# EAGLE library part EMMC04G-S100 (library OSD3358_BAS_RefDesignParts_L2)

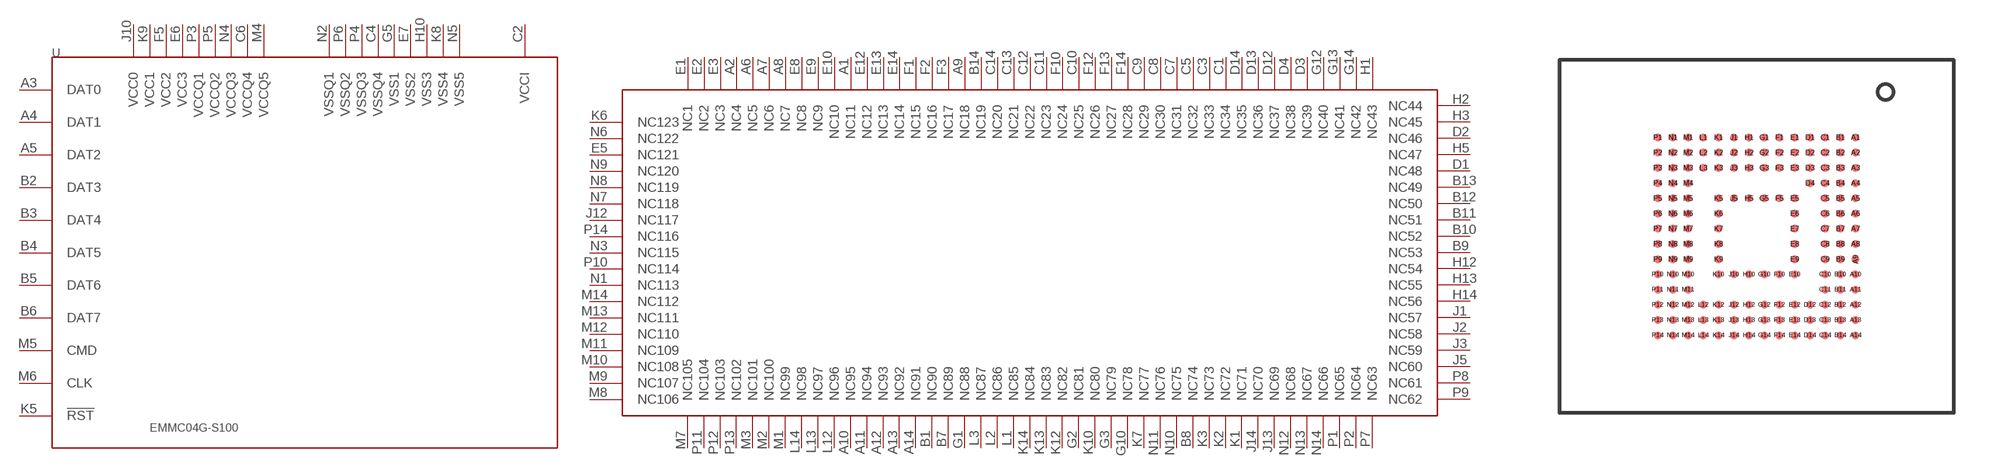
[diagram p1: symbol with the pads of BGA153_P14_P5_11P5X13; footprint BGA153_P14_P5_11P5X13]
Designator prefix U

## EMMC04G-S100  [BGA153_P14_P5_11P5X13]
A1  NC11  nc
A2  NC4  nc
A3  DAT0
A4  DAT1
A5  DAT2
A6  NC5  nc
A7  NC6  nc
A8  NC7  nc
A9  NC18  nc
A10  NC95  nc
A11  NC94  nc
A12  NC93  nc
A13  NC92  nc
A14  NC91  nc
B1  NC90  nc
B2  DAT3
B3  DAT4
B4  DAT5
B5  DAT6
B6  DAT7
B7  NC89  nc
B8  NC74  nc
B9  NC53  nc
B10  NC52  nc
B11  NC51  nc
B12  NC50  nc
B13  NC49  nc
B14  NC19  nc
C1  NC34  nc
C2  VCCI  pwr
C3  NC33  nc
C4  VSSQ4  pwr
C5  NC32  nc
C6  VCCQ4  pwr
C7  NC31  nc
C8  NC30  nc
C9  NC29  nc
C10  NC25  nc
C11  NC23  nc
C12  NC22  nc
C13  NC21  nc
C14  NC20  nc
D1  NC48  nc
D2  NC46  nc
D3  NC39  nc
D4  NC38  nc
D12  NC37  nc
D13  NC36  nc
D14  NC35  nc
E1  NC1  nc
E2  NC2  nc
E3  NC3  nc
E5  NC121  nc
E6  VCC3  pwr
E7  VSS2  pwr
E8  NC8  nc
E9  NC9  nc
E10  NC10  nc
E12  NC12  nc
E13  NC13  nc
E14  NC14  nc
F1  NC15  nc
F2  NC16  nc
F3  NC17  nc
F5  VCC2  pwr
F10  NC24  nc
F12  NC26  nc
F13  NC27  nc
F14  NC28  nc
G1  NC88  nc
G2  NC81  nc
G3  NC79  nc
G5  VSS1  pwr
G10  NC78  nc
G12  NC40  nc
G13  NC41  nc
G14  NC42  nc
H1  NC43  nc
H2  NC44  nc
H3  NC45  nc
H5  NC47  nc
H10  VSS3  pwr
H12  NC54  nc
H13  NC55  nc
H14  NC56  nc
J1  NC57  nc
J2  NC58  nc
J3  NC59  nc
J5  NC60  nc
J10  VCC0  pwr
J12  NC117  nc
J13  NC69  nc
J14  NC70  nc
K1  NC71  nc
K2  NC72  nc
K3  NC73  nc
K5  !RST  in
K6  NC123  nc
K7  NC77  nc
K8  VSS4  pwr
K9  VCC1  pwr
K10  NC80  nc
K12  NC82  nc
K13  NC83  nc
K14  NC84  nc
L1  NC85  nc
L2  NC86  nc
L3  NC87  nc
L12  NC96  nc
L13  NC97  nc
L14  NC98  nc
M1  NC99  nc
M2  NC100  nc
M3  NC101  nc
M4  VCCQ5  pwr
M5  CMD  in
M6  CLK  in
M7  NC105  nc
M8  NC106  nc
M9  NC107  nc
M10  NC108  nc
M11  NC109  nc
M12  NC110  nc
M13  NC111  nc
M14  NC112  nc
N1  NC113  nc
N2  VSSQ1  pwr
N3  NC115  nc
N4  VCCQ3  pwr
N5  VSS5  pwr
N6  NC122  nc
N7  NC118  nc
N8  NC119  nc
N9  NC120  nc
N10  NC75  nc
N11  NC76  nc
N12  NC68  nc
N13  NC67  nc
N14  NC66  nc
P1  NC65  nc
P2  NC64  nc
P3  VCCQ1  pwr
P4  VSSQ3  pwr
P5  VCCQ2  pwr
P6  VSSQ2  pwr
P7  NC63  nc
P8  NC61  nc
P9  NC62  nc
P10  NC114  nc
P11  NC104  nc
P12  NC103  nc
P13  NC102  nc
P14  NC116  nc

## Footprint BGA153_P14_P5_11P5X13 (pad centres in mm)
smd 0.254 x 0.254: A1 3.25,3.25; A2 3.25,2.75; A3 3.25,2.25; A4 3.25,1.75; A5 3.25,1.25; A6 3.25,0.75; A7 3.25,0.25; A8 3.25,-0.25; A9 3.25,-0.75; A10 3.25,-1.25; A11 3.25,-1.75; A12 3.25,-2.25; A13 3.25,-2.75; A14 3.25,-3.25; B1 2.75,3.25; B2 2.75,2.75; B3 2.75,2.25; B4 2.75,1.75; B5 2.75,1.25; B6 2.75,0.75; B7 2.75,0.25; B8 2.75,-0.25; B9 2.75,-0.75; B10 2.75,-1.25; B11 2.75,-1.75; B12 2.75,-2.25; B13 2.75,-2.75; B14 2.75,-3.25; C1 2.25,3.25; C2 2.25,2.75; C3 2.25,2.25; C4 2.25,1.75; C5 2.25,1.25; C6 2.25,0.75; C7 2.25,0.25; C8 2.25,-0.25; C9 2.25,-0.75; C10 2.25,-1.25; C11 2.25,-1.75; C12 2.25,-2.25; C13 2.25,-2.75; C14 2.25,-3.25; D1 1.75,3.25; D2 1.75,2.75; D3 1.75,2.25; D4 1.75,1.75; D12 1.75,-2.25; D13 1.75,-2.75; D14 1.75,-3.25; E1 1.25,3.25; E2 1.25,2.75; E3 1.25,2.25; E5 1.25,1.25; E6 1.25,0.75; E7 1.25,0.25; E8 1.25,-0.25; E9 1.25,-0.75; E10 1.25,-1.25; E12 1.25,-2.25; E13 1.25,-2.75; E14 1.25,-3.25; F1 0.75,3.25; F2 0.75,2.75; F3 0.75,2.25; F5 0.75,1.25; F10 0.75,-1.25; F12 0.75,-2.25; F13 0.75,-2.75; F14 0.75,-3.25; G1 0.25,3.25; G2 0.25,2.75; G3 0.25,2.25; G5 0.25,1.25; G10 0.25,-1.25; G12 0.25,-2.25; G13 0.25,-2.75; G14 0.25,-3.25; H1 -0.25,3.25; H2 -0.25,2.75; H3 -0.25,2.25; H5 -0.25,1.25; H10 -0.25,-1.25; H12 -0.25,-2.25; H13 -0.25,-2.75; H14 -0.25,-3.25; J1 -0.75,3.25; J2 -0.75,2.75; J3 -0.75,2.25; J5 -0.75,1.25; J10 -0.75,-1.25; J12 -0.75,-2.25; J13 -0.75,-2.75; J14 -0.75,-3.25; K1 -1.25,3.25; K2 -1.25,2.75; K3 -1.25,2.25; K5 -1.25,1.25; K6 -1.25,0.75; K7 -1.25,0.25; K8 -1.25,-0.25; K9 -1.25,-0.75; K10 -1.25,-1.25; K12 -1.25,-2.25; K13 -1.25,-2.75; K14 -1.25,-3.25; L1 -1.75,3.25; L2 -1.75,2.75; L3 -1.75,2.25; L12 -1.75,-2.25; L13 -1.75,-2.75; L14 -1.75,-3.25; M1 -2.25,3.25; M2 -2.25,2.75; M3 -2.25,2.25; M4 -2.25,1.75; M5 -2.25,1.25; M6 -2.25,0.75; M7 -2.25,0.25; M8 -2.25,-0.25; M9 -2.25,-0.75; M10 -2.25,-1.25; M11 -2.25,-1.75; M12 -2.25,-2.25; M13 -2.25,-2.75; M14 -2.25,-3.25; N1 -2.75,3.25; N2 -2.75,2.75; N3 -2.75,2.25; N4 -2.75,1.75; N5 -2.75,1.25; N6 -2.75,0.75; N7 -2.75,0.25; N8 -2.75,-0.25; N9 -2.75,-0.75; N10 -2.75,-1.25; N11 -2.75,-1.75; N12 -2.75,-2.25; N13 -2.75,-2.75; N14 -2.75,-3.25; P1 -3.25,3.25; P2 -3.25,2.75; P3 -3.25,2.25; P4 -3.25,1.75; P5 -3.25,1.25; P6 -3.25,0.75; P7 -3.25,0.25; P8 -3.25,-0.25; P9 -3.25,-0.75; P10 -3.25,-1.25; P11 -3.25,-1.75; P12 -3.25,-2.25; P13 -3.25,-2.75; P14 -3.25,-3.25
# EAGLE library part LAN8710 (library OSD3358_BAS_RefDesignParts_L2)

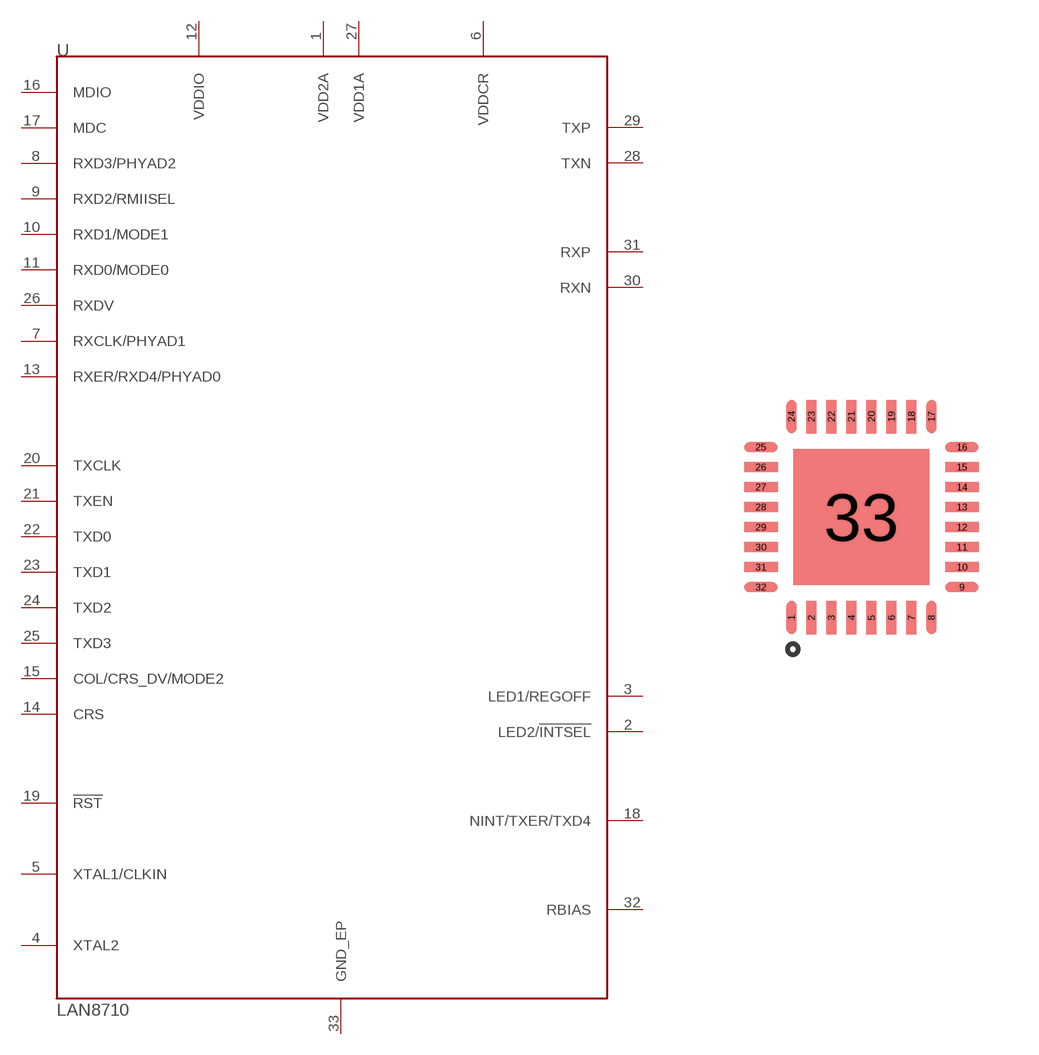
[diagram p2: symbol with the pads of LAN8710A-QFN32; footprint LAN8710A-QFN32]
Designator prefix U

## LAN8710  [LAN8710A-QFN32]
1  VDD2A  pwr
2  LED2/!INTSEL
3  LED1/REGOFF
4  XTAL2  in
5  XTAL1/CLKIN  in
6  VDDCR  pwr
7  RXCLK/PHYAD1
8  RXD3/PHYAD2
9  RXD2/RMIISEL
10  RXD1/MODE1
11  RXD0/MODE0
12  VDDIO  pwr
13  RXER/RXD4/PHYAD0
14  CRS
15  COL/CRS_DV/MODE2
16  MDIO
17  MDC  in
18  NINT/TXER/TXD4
19  !RST
20  TXCLK
21  TXEN  in
22  TXD0  in
23  TXD1  in
24  TXD2  in
25  TXD3  in
26  RXDV
27  VDD1A  pwr
28  TXN
29  TXP
30  RXN
31  RXP
32  RBIAS  pas
33  GND_EP  pwr

## Footprint LAN8710A-QFN32 (pad centres in mm)
smd 0.254 x 0.838: 1 -1.751,-2.515; 2 -1.251,-2.515; 3 -0.751,-2.515; 4 -0.251,-2.515; 5 0.251,-2.515; 6 0.751,-2.515; 7 1.251,-2.515; 8 1.751,-2.515; 17 1.751,2.515; 18 1.251,2.515; 19 0.751,2.515; 20 0.251,2.515; 21 -0.251,2.515; 22 -0.751,2.515; 23 -1.251,2.515; 24 -1.751,2.515
smd 0.838 x 0.254: 9 2.515,-1.751; 10 2.515,-1.251; 11 2.515,-0.751; 12 2.515,-0.251; 13 2.515,0.251; 14 2.515,0.751; 15 2.515,1.251; 16 2.515,1.751; 25 -2.515,1.751; 26 -2.515,1.251; 27 -2.515,0.751; 28 -2.515,0.251; 29 -2.515,-0.251; 30 -2.515,-0.751; 31 -2.515,-1.251; 32 -2.515,-1.751
smd 3.404 x 3.404: 33 0,0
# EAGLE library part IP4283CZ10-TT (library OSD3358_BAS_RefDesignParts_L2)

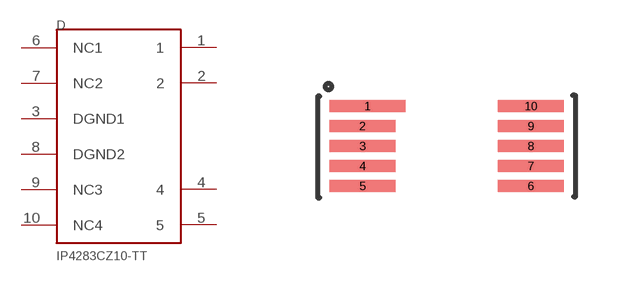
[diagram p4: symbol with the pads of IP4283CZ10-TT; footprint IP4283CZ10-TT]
Designator prefix D

## IP4283CZ10-TT  [IP4283CZ10-TT]
1  1
2  2
3  DGND1
4  4
5  5
6  NC1
7  NC2
8  DGND2
9  NC3
10  NC4

## Footprint IP4283CZ10-TT (pad centres in mm)
smd 1.905 x 0.305: 1 -1.981,1
smd 1.651 x 0.305: 2 -2.108,0.5; 3 -2.108,0; 4 -2.108,-0.5; 5 -2.108,-1; 6 2.108,-1; 7 2.108,-0.5; 8 2.108,0; 9 2.108,0.5; 10 2.108,1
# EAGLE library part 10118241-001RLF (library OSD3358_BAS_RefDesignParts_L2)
Micro-HDMI connector

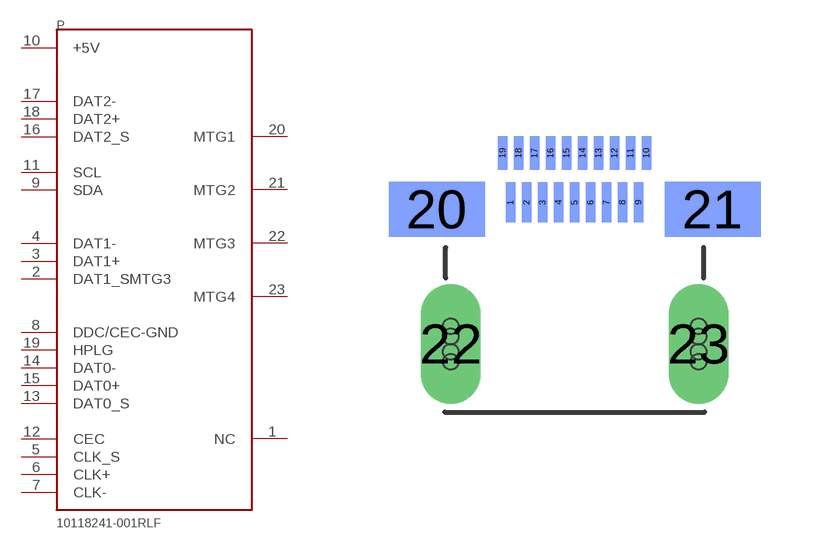
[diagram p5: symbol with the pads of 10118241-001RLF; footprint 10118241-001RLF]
Designator prefix P

## 10118241-001RLF  [10118241-001RLF]
1  NC  nc
2  DAT1_SMTG3
3  DAT1+
4  DAT1-
5  CLK_S
6  CLK+
7  CLK-
8  DDC/CEC-GND
9  SDA
10  +5V  pwr
11  SCL
12  CEC
13  DAT0_S
14  DAT0-
15  DAT0+
16  DAT2_S
17  DAT2-
18  DAT2+
19  HPLG
20  MTG1  pwr
21  MTG2  pwr
22  MTG3  pwr
23  MTG4  pwr

## Footprint 10118241-001RLF (pad centres in mm)
smd 0.23 x 1 bottom: 1 -1.6,3.54; 2 -1.2,3.54; 3 -0.8,3.54; 4 -0.4,3.54; 5 0,3.54; 6 0.4,3.54; 7 0.8,3.54; 8 1.2,3.54; 9 1.6,3.54
smd 0.23 x 0.85 bottom: 10 1.8,4.775; 11 1.4,4.775; 12 1,4.775; 13 0.6,4.775; 14 0.2,4.775; 15 -0.2,4.775; 16 -0.6,4.775; 17 -1,4.775; 18 -1.4,4.775; 19 -1.8,4.775
smd 2.4 x 1.38 bottom: 20 -3.45,3.37; 21 3.45,3.37
drill 0.381 pad 1.499 long: 22 -3.1,0; 23 3.1,0
hole 0.381 at -3.1,0.445
hole 0.381 at -3.1,0.191
hole 0.381 at -3.1,-0.191
hole 0.381 at -3.1,-0.445
hole 0.381 at 3.1,0.445
hole 0.381 at 3.1,0.191
hole 0.381 at 3.1,-0.191
hole 0.381 at 3.1,-0.445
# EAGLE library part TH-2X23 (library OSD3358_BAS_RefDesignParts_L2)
320030002

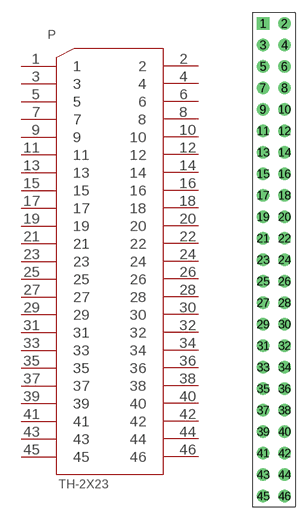
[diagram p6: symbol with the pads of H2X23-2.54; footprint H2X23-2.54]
Designator prefix P

## TH-2X23 (MPN: F185-1223A0ASYC1; VALUE: F185-1223A0ASYC1)  [H2X23-2.54]
1  1
2  2
3  3
4  4
5  5
6  6
7  7
8  8
9  9
10  10
11  11
12  12
13  13
14  14
15  15
16  16
17  17
18  18
19  19
20  20
21  21
22  22
23  23
24  24
25  25
26  26
27  27
28  28
29  29
30  30
31  31
32  32
33  33
34  34
35  35
36  36
37  37
38  38
39  39
40  40
41  41
42  42
43  43
44  44
45  45
46  46

## Footprint H2X23-2.54 (pad centres in mm)
drill 0.762 pad 1.524 square: 1 -1.27,27.94
drill 0.762 pad 1.524: 2 1.27,27.94; 3 -1.27,25.4; 4 1.27,25.4; 5 -1.27,22.86; 6 1.27,22.86; 7 -1.27,20.32; 8 1.27,20.32; 9 -1.27,17.78; 10 1.27,17.78; 11 -1.27,15.24; 12 1.27,15.24; 13 -1.27,12.7; 14 1.27,12.7; 15 -1.27,10.16; 16 1.27,10.16; 17 -1.27,7.62; 18 1.27,7.62; 19 -1.27,5.08; 20 1.27,5.08; 21 -1.27,2.54; 22 1.27,2.54; 23 -1.27,0; 24 1.27,0; 25 -1.27,-2.54; 26 1.27,-2.54; 27 -1.27,-5.08; 28 1.27,-5.08; 29 -1.27,-7.62; 30 1.27,-7.62; 31 -1.27,-10.16; 32 1.27,-10.16; 33 -1.27,-12.7; 34 1.27,-12.7; 35 -1.27,-15.24; 36 1.27,-15.24; 37 -1.27,-17.78; 38 1.27,-17.78; 39 -1.27,-20.32; 40 1.27,-20.32; 41 -1.27,-22.86; 42 1.27,-22.86; 43 -1.27,-25.4; 44 1.27,-25.4; 45 -1.27,-27.94; 46 1.27,-27.94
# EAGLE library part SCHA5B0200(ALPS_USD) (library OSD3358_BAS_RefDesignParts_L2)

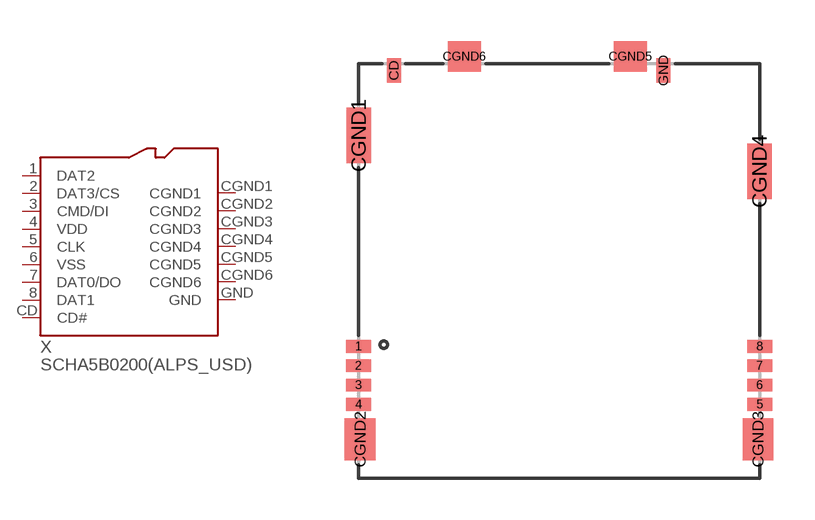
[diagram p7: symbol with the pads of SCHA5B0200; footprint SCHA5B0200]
Designator prefix X

## SCHA5B0200(ALPS_USD)  [SCHA5B0200]
1  DAT2
2  DAT3/CS
3  CMD/DI
4  VDD
5  CLK
6  VSS
7  DAT0/DO
8  DAT1
CD  CD#
CGND1  CGND1
CGND2  CGND2
CGND3  CGND3
CGND4  CGND4
CGND5  CGND5
CGND6  CGND6
GND  GND

## Footprint SCHA5B0200 (pad centres in mm)
smd 0.915 x 0.458: 1 -7.257,3.365; 2 -7.257,2.665; 3 -7.257,1.965; 4 -7.257,1.265; 5 7.257,1.265; 6 7.257,1.965; 7 7.257,2.665; 8 7.257,3.365
smd 0.51 x 0.887: CD -5.975,13.354; GND 3.775,13.354
smd 0.891 x 2.007: CGND1 -7.25,11; CGND4 7.25,9.7
smd 1.117 x 1.525: CGND2 -7.196,0; CGND3 7.196,0
smd 1.192 x 1.092: CGND5 2.575,13.853; CGND6 -3.425,13.853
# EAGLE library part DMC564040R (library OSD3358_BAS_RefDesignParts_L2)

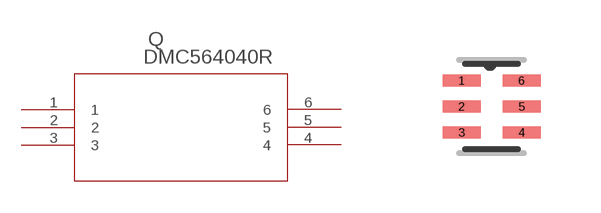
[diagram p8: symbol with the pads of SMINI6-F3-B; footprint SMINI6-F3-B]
Designator prefix Q

## DMC564040R (COPYRIGHT: Copyright (C) 2015 Accelerated Designs. All rights reserved; MANUFACTURER_PART_NUMBER: DMC564040R; VENDOR: Panasonic)  [SMINI6-F3-B]
1  1  pas
2  2  pas
3  3  pas
4  4  pas
5  5  pas
6  6  pas

## Footprint SMINI6-F3-B (pad centres in mm)
smd 0.95 x 0.305: 1 -0.75,0.65; 2 -0.75,0; 3 -0.75,-0.65; 4 0.75,-0.65; 5 0.75,0; 6 0.75,0.65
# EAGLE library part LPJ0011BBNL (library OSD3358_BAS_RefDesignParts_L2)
Ethernet Connector MagJack (R) Source: www.stewartconnector.com .. si-50170.pdf

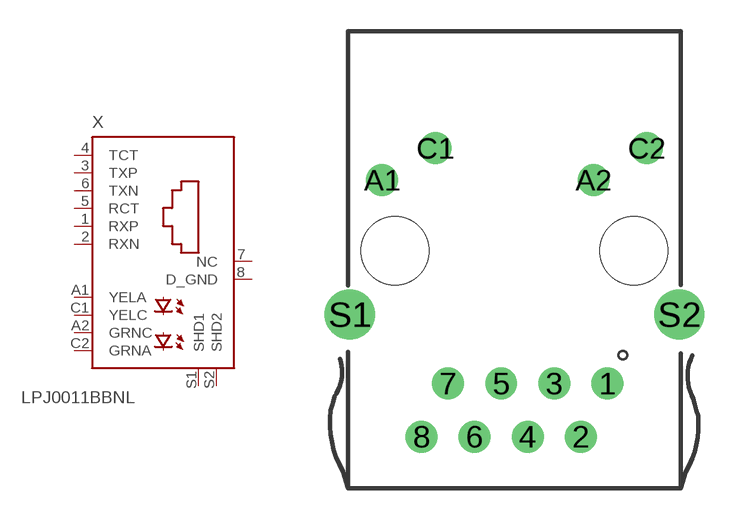
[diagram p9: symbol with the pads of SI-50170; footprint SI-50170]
Designator prefix X

## LPJ0011BBNL (OC_FARNELL: unknown; OC_NEWARK: unknown)  [SI-50170]
1  RXP  pas
2  RXN  pas
3  TXP  pas
4  TCT  pas
5  RCT  pas
6  TXN  pas
7  NC  pas
8  D_GND  pas
A1  YELA  pas
A2  GRNC  pas
C1  YELC  pas
C2  GRNA  pas
S1  SHD1  pas
S2  SHD2  pas

## Footprint SI-50170 (pad centres in mm)
Ethernet Connector (MagJack) Source: si-50170.pdf
drill 1.016 pad 1.524: 1 4.445,-6.413; 2 3.175,-8.954; 3 1.905,-6.413; 4 0.635,-8.954; 5 -0.635,-6.413; 6 -1.905,-8.954; 7 -3.175,-6.413; 8 -4.445,-8.954; A1 -6.325,3.315; A2 3.785,3.315; C1 -3.785,4.839; C2 6.325,4.839
drill 1.6 pad 2.286: S1 -7.874,-3.111; S2 7.874,-3.111
hole 3.251 at -5.715,-0.064
hole 3.251 at 5.715,-0.064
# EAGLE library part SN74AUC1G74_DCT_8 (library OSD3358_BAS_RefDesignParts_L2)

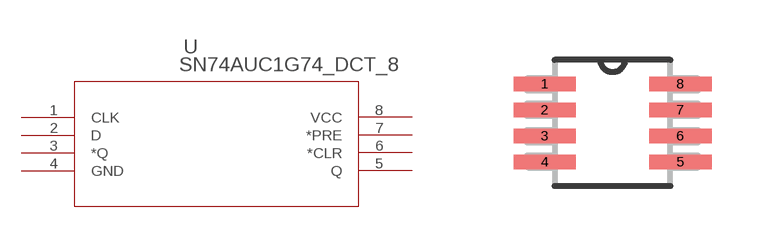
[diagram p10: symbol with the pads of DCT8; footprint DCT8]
Designator prefix U

## SN74AUC1G74_DCT_8 (DATASHEETURL: http://www.ti.com/lit/gpn/SN74AUC1G74; FAMILY_NAME: LL FLIP-FLOP; GENERIC_PART_NUMBER: SN74AUC1G74; INDUSTRY_STD_PKG_TYPE: SM8; MANUFACTURER: Texas Instruments; MANUFACTURER_PART_NUMBER: sn74auc1g74_dct_8; PACKAGE_DESIGNATOR: DCT; PIN_COUNT: 8; VENDOR: Texas Instruments)  [DCT8]
1  CLK  in
2  D  in
3  *Q  out
4  GND  pwr
5  Q  out
6  *CLR  in
7  *PRE  in
8  VCC  pwr

## Footprint DCT8 (pad centres in mm)
smd 1.562 x 0.356: 1 -1.695,0.975; 2 -1.695,0.325; 3 -1.695,-0.325; 4 -1.695,-0.975; 5 1.695,-0.975; 6 1.695,-0.325; 7 1.695,0.325; 8 1.695,0.975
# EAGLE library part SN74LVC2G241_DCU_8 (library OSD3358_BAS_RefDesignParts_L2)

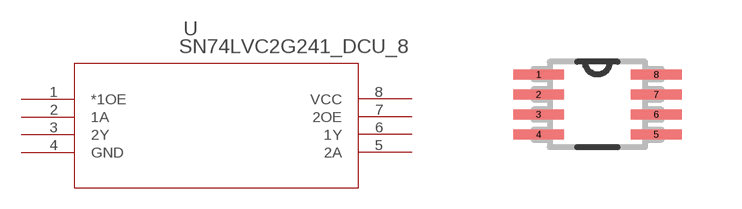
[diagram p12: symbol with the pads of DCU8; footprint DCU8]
Designator prefix U

## SN74LVC2G241_DCU_8 (DATASHEETURL: http://www.ti.com/lit/gpn/SN74LVC2G241; FAMILY_NAME: LL BUFFER AND DRIVER WITH 3-STATE OUTPUT; GENERIC_PART_NUMBER: SN74LVC2G241; INDUSTRY_STD_PKG_TYPE: US8; MANUFACTURER: Texas Instruments; MANUFACTURER_PART_NUMBER: sn74lvc2g241_dcu_8; PACKAGE_DESIGNATOR: DCU; PIN_COUNT: 8; VENDOR: Texas Instruments)  [DCU8]
1  *1OE  in
2  1A  in
3  2Y  out
4  GND  pwr
5  2A  in
6  1Y  out
7  2OE  in
8  VCC  pwr

## Footprint DCU8 (pad centres in mm)
smd 1.27 x 0.254: 1 -1.473,0.749; 2 -1.473,0.249; 3 -1.473,-0.249; 4 -1.473,-0.749; 5 1.473,-0.749; 6 1.473,-0.249; 7 1.473,0.249; 8 1.473,0.749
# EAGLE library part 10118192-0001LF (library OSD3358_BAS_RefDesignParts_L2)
Amphenol FCI Micro USB Type B Complete Surface Mount (SMT) no guide holes

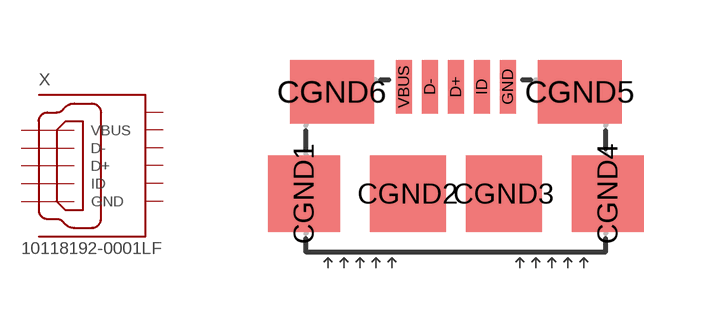
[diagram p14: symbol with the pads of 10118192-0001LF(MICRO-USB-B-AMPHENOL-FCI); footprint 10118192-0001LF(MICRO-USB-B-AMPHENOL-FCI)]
Designator prefix X

## 10118192-0001LF  [10118192-0001LF(MICRO-USB-B-AMPHENOL-FCI)]
CGND1  SGND1
CGND2  SGND2
CGND3  SGND3
CGND4  SGND4
CGND5  SGND5
CGND6  SGND6
D+  D+  in
D-  D-  in
GND  GND  in
ID  ID  in
VBUS  VBUS  in

## Footprint 10118192-0001LF(MICRO-USB-B-AMPHENOL-FCI) (pad centres in mm)
smd 1.8 x 1.9: CGND1 -3.8,0; CGND4 3.8,0
smd 1.9 x 1.9: CGND2 -1.2,0; CGND3 1.2,0
smd 2.1 x 1.6: CGND5 3.1,2.55; CGND6 -3.1,2.55
smd 0.4 x 1.35: D+ 0,2.675; D- -0.65,2.675; GND 1.3,2.675; ID 0.65,2.675; VBUS -1.3,2.675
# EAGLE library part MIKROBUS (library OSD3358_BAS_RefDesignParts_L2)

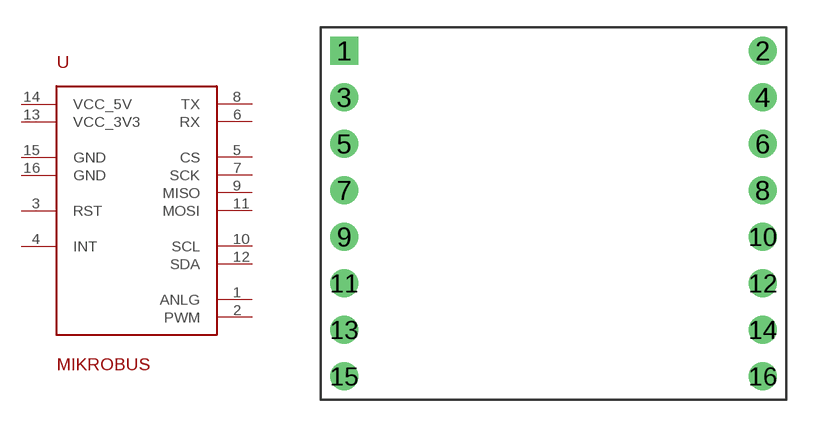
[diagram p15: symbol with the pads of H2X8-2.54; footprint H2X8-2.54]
Designator prefix -

## MIKROBUS  [H2X8-2.54]
1  ANLG
2  PWM
3  RST
4  INT
5  CS
6  RX
7  SCK
8  TX
9  MISO
10  SCL
11  MOSI
12  SDA
13  VCC_3V3
14  VCC_5V
15  GND
16  GND

## Footprint H2X8-2.54 (pad centres in mm)
drill 0.762 pad 1.524 square: 1 -11.684,8.89
drill 0.762 pad 1.524: 2 11.176,8.89; 3 -11.684,6.35; 4 11.176,6.35; 5 -11.684,3.81; 6 11.176,3.81; 7 -11.684,1.27; 8 11.176,1.27; 9 -11.684,-1.27; 10 11.176,-1.27; 11 -11.684,-3.81; 12 11.176,-3.81; 13 -11.684,-6.35; 14 11.176,-6.35; 15 -11.684,-8.89; 16 11.176,-8.89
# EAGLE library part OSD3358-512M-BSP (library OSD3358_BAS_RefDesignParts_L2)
Octavo Systems LLC OSD335x Family SiP: 21mm x 21mm, 1.27mm pitch 256 pin BGA contains AM3358, 512MB DDR3, TPS65217, TL5209, EEPROM and passives. Commerical Temperature: 0C to 85C.

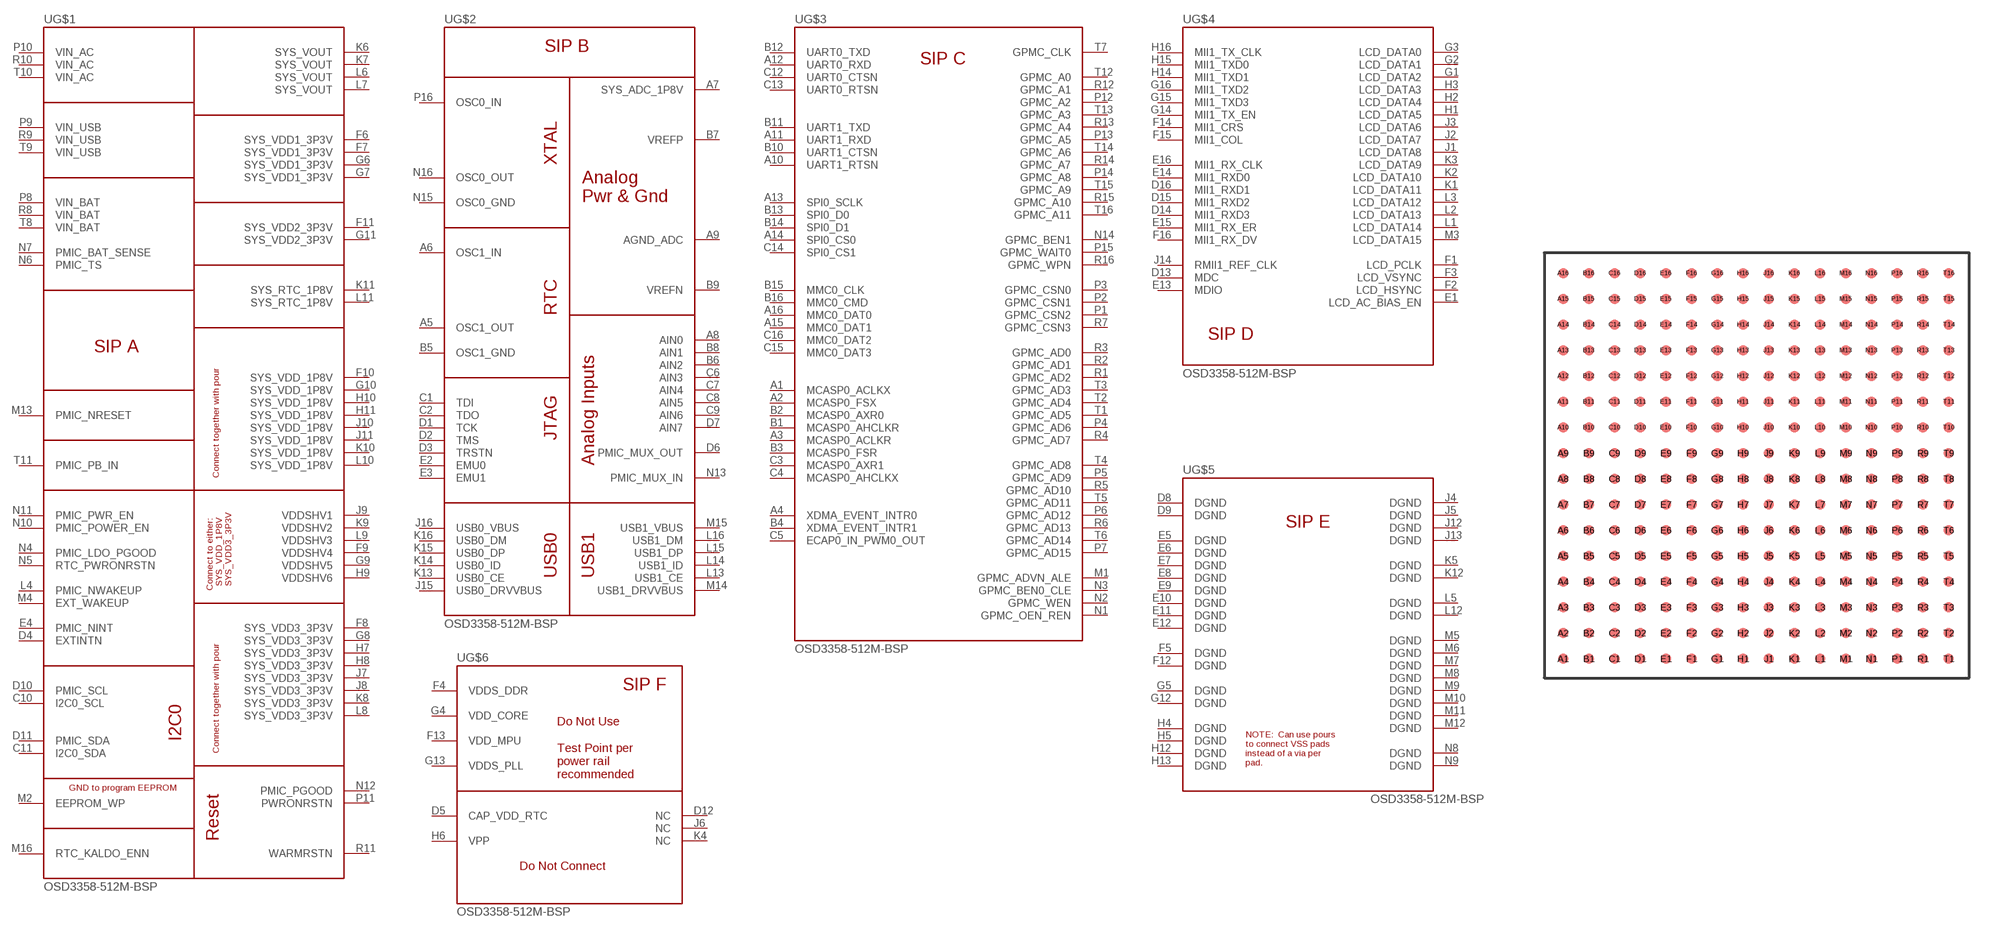
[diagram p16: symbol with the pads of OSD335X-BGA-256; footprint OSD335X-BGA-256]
Designator prefix -; gates G$1=OSD335X-SP-LOGICAL-A G$2=OSD335X-SP-LOGICAL-B G$3=OSD335X-SP-LOGICAL-C G$4=OSD335X-SP-LOGICAL-D G$5=OSD335X-SP-LOGICAL-E G$6=OSD335X-SP-LOGICAL-F

## OSD3358-512M-BSP  [OSD335X-BGA-256]
A1  G$3:MCASP0_ACLKX
A2  G$3:MCASP0_FSX
A3  G$3:MCASP0_ACLKR
A4  G$3:XDMA_EVENT_INTR0
A5  G$2:OSC1_OUT
A6  G$2:OSC1_IN
A7  G$2:SYS_ADC_1P8V
A8  G$2:AIN0
A9  G$2:AGND_ADC
A10  G$3:UART1_RTSN
A11  G$3:UART1_RXD
A12  G$3:UART0_RXD
A13  G$3:SPI0_SCLK
A14  G$3:SPI0_CS0
A15  G$3:MMC0_DAT1
A16  G$3:MMC0_DAT0
B1  G$3:MCASP0_AHCLKR
B2  G$3:MCASP0_AXR0
B3  G$3:MCASP0_FSR
B4  G$3:XDMA_EVENT_INTR1
B5  G$2:OSC1_GND
B6  G$2:AIN2
B7  G$2:VREFP
B8  G$2:AIN1
B9  G$2:VREFN
B10  G$3:UART1_CTSN
B11  G$3:UART1_TXD
B12  G$3:UART0_TXD
B13  G$3:SPI0_D0
B14  G$3:SPI0_D1
B15  G$3:MMC0_CLK
B16  G$3:MMC0_CMD
C1  G$2:TDI
C2  G$2:TDO
C3  G$3:MCASP0_AXR1
C4  G$3:MCASP0_AHCLKX
C5  G$3:ECAP0_IN_PWM0_OUT
C6  G$2:AIN3
C7  G$2:AIN4
C8  G$2:AIN5
C9  G$2:AIN6
C10  G$1:I2C0_SCL
C11  G$1:I2C0_SDA
C12  G$3:UART0_CTSN
C13  G$3:UART0_RTSN
C14  G$3:SPI0_CS1
C15  G$3:MMC0_DAT3
C16  G$3:MMC0_DAT2
D1  G$2:TCK
D2  G$2:TMS
D3  G$2:TRSTN
D4  G$1:EXTINTN
D5  G$6:CAP_VDD_RTC
D6  G$2:PMIC_MUX_OUT
D7  G$2:AIN7
D8  G$5:DGND
D9  G$5:DGND
D10  G$1:PMIC_SCL
D11  G$1:PMIC_SDA
D12  G$6:NC
D13  G$4:MDC
D14  G$4:MII1_RXD3
D15  G$4:MII1_RXD2
D16  G$4:MII1_RXD1
E1  G$4:LCD_AC_BIAS_EN
E2  G$2:EMU0
E3  G$2:EMU1
E4  G$1:PMIC_NINT  out
E5  G$5:DGND
E6  G$5:DGND
E7  G$5:DGND
E8  G$5:DGND
E9  G$5:DGND
E10  G$5:DGND
E11  G$5:DGND
E12  G$5:DGND
E13  G$4:MDIO
E14  G$4:MII1_RXD0
E15  G$4:MII1_RX_ER
E16  G$4:MII1_RX_CLK
F1  G$4:LCD_PCLK
F2  G$4:LCD_HSYNC
F3  G$4:LCD_VSYNC
F4  G$6:VDDS_DDR
F5  G$5:DGND
F6  G$1:SYS_VDD1_3P3V  pwr
F7  G$1:SYS_VDD1_3P3V  pwr
F8  G$1:SYS_VDD3_3P3V  pwr
F9  G$1:VDDSHV4  pwr
F10  G$1:SYS_VDD_1P8V  pwr
F11  G$1:SYS_VDD2_3P3V  pwr
F12  G$5:DGND
F13  G$6:VDD_MPU
F14  G$4:MII1_CRS
F15  G$4:MII1_COL
F16  G$4:MII1_RX_DV
G1  G$4:LCD_DATA2
G2  G$4:LCD_DATA1
G3  G$4:LCD_DATA0
G4  G$6:VDD_CORE
G5  G$5:DGND
G6  G$1:SYS_VDD1_3P3V  pwr
G7  G$1:SYS_VDD1_3P3V  pwr
G8  G$1:SYS_VDD3_3P3V  pwr
G9  G$1:VDDSHV5  pwr
G10  G$1:SYS_VDD_1P8V  pwr
G11  G$1:SYS_VDD2_3P3V  pwr
G12  G$5:DGND
G13  G$6:VDDS_PLL
G14  G$4:MII1_TX_EN
G15  G$4:MII1_TXD3
G16  G$4:MII1_TXD2
H1  G$4:LCD_DATA5
H2  G$4:LCD_DATA4
H3  G$4:LCD_DATA3
H4  G$5:DGND
H5  G$5:DGND
H6  G$6:VPP
H7  G$1:SYS_VDD3_3P3V  pwr
H8  G$1:SYS_VDD3_3P3V  pwr
H9  G$1:VDDSHV6  pwr
H10  G$1:SYS_VDD_1P8V  pwr
H11  G$1:SYS_VDD_1P8V  pwr
H12  G$5:DGND
H13  G$5:DGND
H14  G$4:MII1_TXD1
H15  G$4:MII1_TXD0
H16  G$4:MII1_TX_CLK
J1  G$4:LCD_DATA8
J2  G$4:LCD_DATA7
J3  G$4:LCD_DATA6
J4  G$5:DGND
J5  G$5:DGND
J6  G$6:NC
J7  G$1:SYS_VDD3_3P3V  pwr
J8  G$1:SYS_VDD3_3P3V  pwr
J9  G$1:VDDSHV1  pwr
J10  G$1:SYS_VDD_1P8V  pwr
J11  G$1:SYS_VDD_1P8V  pwr
J12  G$5:DGND
J13  G$5:DGND
J14  G$4:RMII1_REF_CLK
J15  G$2:USB0_DRVVBUS
J16  G$2:USB0_VBUS
K1  G$4:LCD_DATA11
K2  G$4:LCD_DATA10
K3  G$4:LCD_DATA9
K4  G$6:NC
K5  G$5:DGND
K6  G$1:SYS_VOUT  pwr
K7  G$1:SYS_VOUT  pwr
K8  G$1:SYS_VDD3_3P3V  pwr
K9  G$1:VDDSHV2  pwr
K10  G$1:SYS_VDD_1P8V  pwr
K11  G$1:SYS_RTC_1P8V  pwr
K12  G$5:DGND
K13  G$2:USB0_CE
K14  G$2:USB0_ID
K15  G$2:USB0_DP
K16  G$2:USB0_DM
L1  G$4:LCD_DATA14
L2  G$4:LCD_DATA13
L3  G$4:LCD_DATA12
L4  G$1:PMIC_NWAKEUP  out
L5  G$5:DGND
L6  G$1:SYS_VOUT  pwr
L7  G$1:SYS_VOUT  pwr
L8  G$1:SYS_VDD3_3P3V  pwr
L9  G$1:VDDSHV3  pwr
L10  G$1:SYS_VDD_1P8V  pwr
L11  G$1:SYS_RTC_1P8V  pwr
L12  G$5:DGND
L13  G$2:USB1_CE
L14  G$2:USB1_ID
L15  G$2:USB1_DP
L16  G$2:USB1_DM
M1  G$3:GPMC_ADVN_ALE
M2  G$1:EEPROM_WP
M3  G$4:LCD_DATA15
M4  G$1:EXT_WAKEUP
M5  G$5:DGND
M6  G$5:DGND
M7  G$5:DGND
M8  G$5:DGND
M9  G$5:DGND
M10  G$5:DGND
M11  G$5:DGND
M12  G$5:DGND
M13  G$1:PMIC_NRESET
M14  G$2:USB1_DRVVBUS
M15  G$2:USB1_VBUS
M16  G$1:RTC_KALDO_ENN
N1  G$3:GPMC_OEN_REN
N2  G$3:GPMC_WEN
N3  G$3:GPMC_BEN0_CLE
N4  G$1:PMIC_LDO_PGOOD  out
N5  G$1:RTC_PWRONRSTN
N6  G$1:PMIC_TS
N7  G$1:PMIC_BAT_SENSE
N8  G$5:DGND
N9  G$5:DGND
N10  G$1:PMIC_POWER_EN  out
N11  G$1:PMIC_PWR_EN  in
N12  G$1:PMIC_PGOOD  out
N13  G$2:PMIC_MUX_IN
N14  G$3:GPMC_BEN1
N15  G$2:OSC0_GND
N16  G$2:OSC0_OUT
P1  G$3:GPMC_CSN2
P2  G$3:GPMC_CSN1
P3  G$3:GPMC_CSN0
P4  G$3:GPMC_AD6
P5  G$3:GPMC_AD9
P6  G$3:GPMC_AD12
P7  G$3:GPMC_AD15
P8  G$1:VIN_BAT  pwr
P9  G$1:VIN_USB  pwr
P10  G$1:VIN_AC  pwr
P11  G$1:PWRONRSTN
P12  G$3:GPMC_A2
P13  G$3:GPMC_A5
P14  G$3:GPMC_A8
P15  G$3:GPMC_WAIT0
P16  G$2:OSC0_IN
R1  G$3:GPMC_AD2
R2  G$3:GPMC_AD1
R3  G$3:GPMC_AD0
R4  G$3:GPMC_AD7
R5  G$3:GPMC_AD10
R6  G$3:GPMC_AD13
R7  G$3:GPMC_CSN3
R8  G$1:VIN_BAT  pwr
R9  G$1:VIN_USB  pwr
R10  G$1:VIN_AC  pwr
R11  G$1:WARMRSTN
R12  G$3:GPMC_A1
R13  G$3:GPMC_A4
R14  G$3:GPMC_A7
R15  G$3:GPMC_A10
R16  G$3:GPMC_WPN
T1  G$3:GPMC_AD5
T2  G$3:GPMC_AD4
T3  G$3:GPMC_AD3
T4  G$3:GPMC_AD8
T5  G$3:GPMC_AD11
T6  G$3:GPMC_AD14
T7  G$3:GPMC_CLK
T8  G$1:VIN_BAT  pwr
T9  G$1:VIN_USB  pwr
T10  G$1:VIN_AC  pwr
T11  G$1:PMIC_PB_IN
T12  G$3:GPMC_A0
T13  G$3:GPMC_A3
T14  G$3:GPMC_A6
T15  G$3:GPMC_A9
T16  G$3:GPMC_A11

## Footprint OSD335X-BGA-256 (pad centres in mm)
smd 0.5 x 0.5: A1 -9.525,-9.525; A2 -9.525,-8.255; A3 -9.525,-6.985; A4 -9.525,-5.715; A5 -9.525,-4.445; A6 -9.525,-3.175; A7 -9.525,-1.905; A8 -9.525,-0.635; A9 -9.525,0.635; A10 -9.525,1.905; A11 -9.525,3.175; A12 -9.525,4.445; A13 -9.525,5.715; A14 -9.525,6.985; A15 -9.525,8.255; A16 -9.525,9.525; B1 -8.255,-9.525; B2 -8.255,-8.255; B3 -8.255,-6.985; B4 -8.255,-5.715; B5 -8.255,-4.445; B6 -8.255,-3.175; B7 -8.255,-1.905; B8 -8.255,-0.635; B9 -8.255,0.635; B10 -8.255,1.905; B11 -8.255,3.175; B12 -8.255,4.445; B13 -8.255,5.715; B14 -8.255,6.985; B15 -8.255,8.255; B16 -8.255,9.525; C1 -6.985,-9.525; C2 -6.985,-8.255; C3 -6.985,-6.985; C4 -6.985,-5.715; C5 -6.985,-4.445; C6 -6.985,-3.175; C7 -6.985,-1.905; C8 -6.985,-0.635; C9 -6.985,0.635; C10 -6.985,1.905; C11 -6.985,3.175; C12 -6.985,4.445; C13 -6.985,5.715; C14 -6.985,6.985; C15 -6.985,8.255; C16 -6.985,9.525; D1 -5.715,-9.525; D2 -5.715,-8.255; D3 -5.715,-6.985; D4 -5.715,-5.715; D5 -5.715,-4.445; D6 -5.715,-3.175; D7 -5.715,-1.905; D8 -5.715,-0.635; D9 -5.715,0.635; D10 -5.715,1.905; D11 -5.715,3.175; D12 -5.715,4.445; D13 -5.715,5.715; D14 -5.715,6.985; D15 -5.715,8.255; D16 -5.715,9.525; E1 -4.445,-9.525; E2 -4.445,-8.255; E3 -4.445,-6.985; E4 -4.445,-5.715; E5 -4.445,-4.445; E6 -4.445,-3.175; E7 -4.445,-1.905; E8 -4.445,-0.635; E9 -4.445,0.635; E10 -4.445,1.905; E11 -4.445,3.175; E12 -4.445,4.445; E13 -4.445,5.715; E14 -4.445,6.985; E15 -4.445,8.255; E16 -4.445,9.525; F1 -3.175,-9.525; F2 -3.175,-8.255; F3 -3.175,-6.985; F4 -3.175,-5.715; F5 -3.175,-4.445; F6 -3.175,-3.175; F7 -3.175,-1.905; F8 -3.175,-0.635; F9 -3.175,0.635; F10 -3.175,1.905; F11 -3.175,3.175; F12 -3.175,4.445; F13 -3.175,5.715; F14 -3.175,6.985; F15 -3.175,8.255; F16 -3.175,9.525; G1 -1.905,-9.525; G2 -1.905,-8.255; G3 -1.905,-6.985; G4 -1.905,-5.715; G5 -1.905,-4.445; G6 -1.905,-3.175; G7 -1.905,-1.905; G8 -1.905,-0.635; G9 -1.905,0.635; G10 -1.905,1.905; G11 -1.905,3.175; G12 -1.905,4.445; G13 -1.905,5.715; G14 -1.905,6.985; G15 -1.905,8.255; G16 -1.905,9.525; H1 -0.635,-9.525; H2 -0.635,-8.255; H3 -0.635,-6.985; H4 -0.635,-5.715; H5 -0.635,-4.445; H6 -0.635,-3.175; H7 -0.635,-1.905; H8 -0.635,-0.635; H9 -0.635,0.635; H10 -0.635,1.905; H11 -0.635,3.175; H12 -0.635,4.445; H13 -0.635,5.715; H14 -0.635,6.985; H15 -0.635,8.255; H16 -0.635,9.525; J1 0.635,-9.525; J2 0.635,-8.255; J3 0.635,-6.985; J4 0.635,-5.715; J5 0.635,-4.445; J6 0.635,-3.175; J7 0.635,-1.905; J8 0.635,-0.635; J9 0.635,0.635; J10 0.635,1.905; J11 0.635,3.175; J12 0.635,4.445; J13 0.635,5.715; J14 0.635,6.985; J15 0.635,8.255; J16 0.635,9.525; K1 1.905,-9.525; K2 1.905,-8.255; K3 1.905,-6.985; K4 1.905,-5.715; K5 1.905,-4.445; K6 1.905,-3.175; K7 1.905,-1.905; K8 1.905,-0.635; K9 1.905,0.635; K10 1.905,1.905; K11 1.905,3.175; K12 1.905,4.445; K13 1.905,5.715; K14 1.905,6.985; K15 1.905,8.255; K16 1.905,9.525; L1 3.175,-9.525; L2 3.175,-8.255; L3 3.175,-6.985; L4 3.175,-5.715; L5 3.175,-4.445; L6 3.175,-3.175; L7 3.175,-1.905; L8 3.175,-0.635; L9 3.175,0.635; L10 3.175,1.905; L11 3.175,3.175; L12 3.175,4.445; L13 3.175,5.715; L14 3.175,6.985; L15 3.175,8.255; L16 3.175,9.525; M1 4.445,-9.525; M2 4.445,-8.255; M3 4.445,-6.985; M4 4.445,-5.715; M5 4.445,-4.445; M6 4.445,-3.175; M7 4.445,-1.905; M8 4.445,-0.635; M9 4.445,0.635; M10 4.445,1.905; M11 4.445,3.175; M12 4.445,4.445; M13 4.445,5.715; M14 4.445,6.985; M15 4.445,8.255; M16 4.445,9.525; N1 5.715,-9.525; N2 5.715,-8.255; N3 5.715,-6.985; N4 5.715,-5.715; N5 5.715,-4.445; N6 5.715,-3.175; N7 5.715,-1.905; N8 5.715,-0.635; N9 5.715,0.635; N10 5.715,1.905; N11 5.715,3.175; N12 5.715,4.445; N13 5.715,5.715; N14 5.715,6.985; N15 5.715,8.255; N16 5.715,9.525; P1 6.985,-9.525; P2 6.985,-8.255; P3 6.985,-6.985; P4 6.985,-5.715; P5 6.985,-4.445; P6 6.985,-3.175; P7 6.985,-1.905; P8 6.985,-0.635; P9 6.985,0.635; P10 6.985,1.905; P11 6.985,3.175; P12 6.985,4.445; P13 6.985,5.715; P14 6.985,6.985; P15 6.985,8.255; P16 6.985,9.525; R1 8.255,-9.525; R2 8.255,-8.255; R3 8.255,-6.985; R4 8.255,-5.715; R5 8.255,-4.445; R6 8.255,-3.175; R7 8.255,-1.905; R8 8.255,-0.635; R9 8.255,0.635; R10 8.255,1.905; R11 8.255,3.175; R12 8.255,4.445; R13 8.255,5.715; R14 8.255,6.985; R15 8.255,8.255; R16 8.255,9.525; T1 9.525,-9.525; T2 9.525,-8.255; T3 9.525,-6.985; T4 9.525,-5.715; T5 9.525,-4.445; T6 9.525,-3.175; T7 9.525,-1.905; T8 9.525,-0.635; T9 9.525,0.635; T10 9.525,1.905; T11 9.525,3.175; T12 9.525,4.445; T13 9.525,5.715; T14 9.525,6.985; T15 9.525,8.255; T16 9.525,9.525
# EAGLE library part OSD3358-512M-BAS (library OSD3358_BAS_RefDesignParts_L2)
Octavo Systems LLC OSD335x Family SiP: 27mm x 27mm, 1.27mm pitch 400 pin BGA contains AM3358, 512MB DDR3, TPS65217, TL5209 and passives. Commerical Temperature: 0C to 85C.

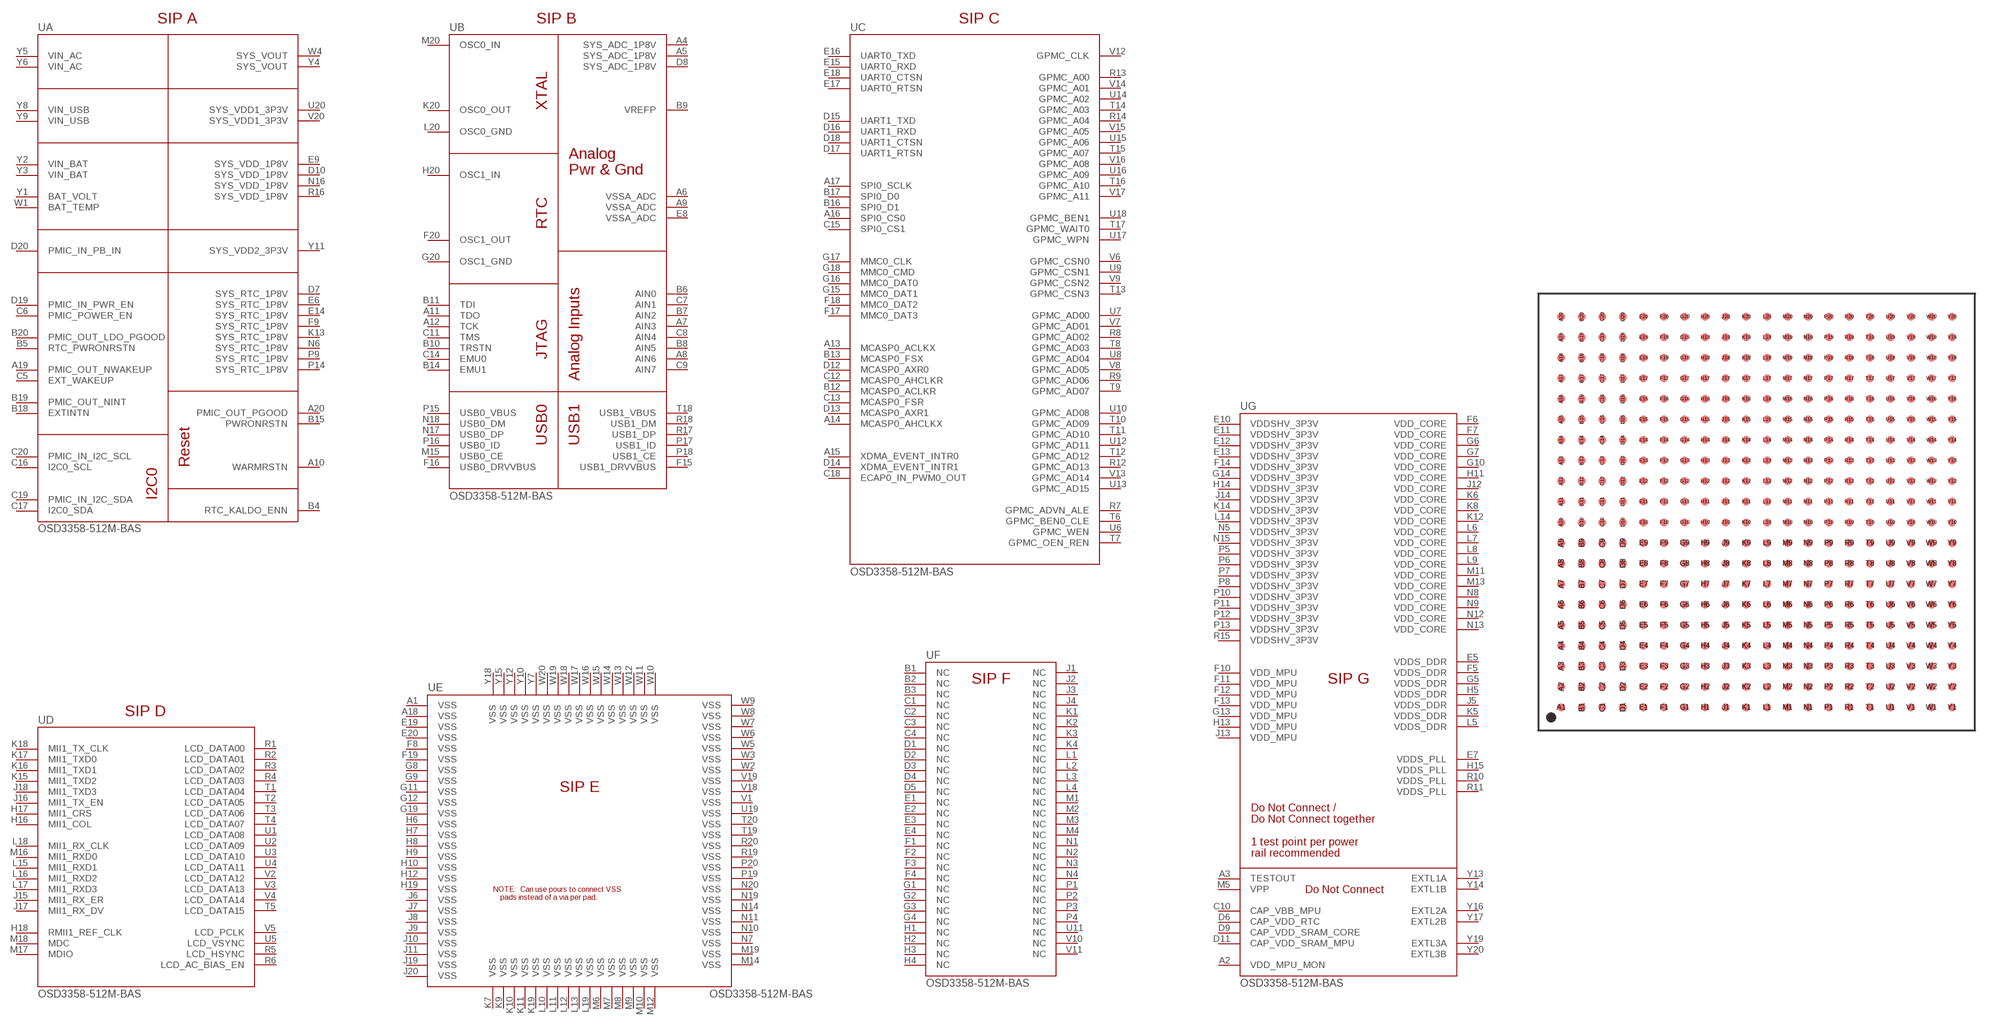
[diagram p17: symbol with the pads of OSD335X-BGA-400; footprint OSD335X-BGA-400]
Designator prefix U; gates A=OSD335X-BASE-LOGICAL-A-1 B=OSD335X-BASE-LOGICAL-B-1 C=OSD335X-BASE-LOGICAL-C-1 D=OSD335X-BASE-LOGICAL-D-1 E=OSD335X-BASE-LOGICAL-E-1 F=OSD335X-BASE-LOGICAL-F-1 G=OSD335X-BASE-LOGICAL-G-1

## OSD3358-512M-BAS  [OSD335X-BGA-400]
A1  E:VSS
A2  G:VDD_MPU_MON
A3  G:TESTOUT
A4  B:SYS_ADC_1P8V
A5  B:SYS_ADC_1P8V
A6  B:VSSA_ADC
A7  B:AIN3
A8  B:AIN6
A9  B:VSSA_ADC
A10  A:WARMRSTN
A11  B:TDO
A12  B:TCK
A13  C:MCASP0_ACLKX
A14  C:MCASP0_AHCLKX
A15  C:XDMA_EVENT_INTR0
A16  C:SPI0_CS0
A17  C:SPI0_SCLK
A18  E:VSS
A19  A:PMIC_OUT_NWAKEUP  out
A20  A:PMIC_OUT_PGOOD  out
B1  F:NC
B2  F:NC
B3  F:NC
B4  A:RTC_KALDO_ENN
B5  A:RTC_PWRONRSTN
B6  B:AIN0
B7  B:AIN2
B8  B:AIN5
B9  B:VREFP
B10  B:TRSTN
B11  B:TDI
B12  C:MCASP0_ACLKR
B13  C:MCASP0_FSX
B14  B:EMU1
B15  A:PWRONRSTN
B16  C:SPI0_D1
B17  C:SPI0_D0
B18  A:EXTINTN
B19  A:PMIC_OUT_NINT  out
B20  A:PMIC_OUT_LDO_PGOOD  out
C1  F:NC
C2  F:NC
C3  F:NC
C4  F:NC
C5  A:EXT_WAKEUP
C6  A:PMIC_POWER_EN  out
C7  B:AIN1
C8  B:AIN4
C9  B:AIN7
C10  G:CAP_VBB_MPU
C11  B:TMS
C12  C:MCASP0_AHCLKR
C13  C:MCASP0_FSR
C14  B:EMU0
C15  C:SPI0_CS1
C16  A:I2C0_SCL
C17  A:I2C0_SDA
C18  C:ECAP0_IN_PWM0_OUT
C19  A:PMIC_IN_I2C_SDA
C20  A:PMIC_IN_I2C_SCL
D1  F:NC
D2  F:NC
D3  F:NC
D4  F:NC
D5  F:NC
D6  G:CAP_VDD_RTC
D7  A:SYS_RTC_1P8V
D8  B:SYS_ADC_1P8V
D9  G:CAP_VDD_SRAM_CORE
D10  A:SYS_VDD_1P8V
D11  G:CAP_VDD_SRAM_MPU
D12  C:MCASP0_AXR0
D13  C:MCASP0_AXR1
D14  C:XDMA_EVENT_INTR1
D15  C:UART1_TXD
D16  C:UART1_RXD
D17  C:UART1_RTSN
D18  C:UART1_CTSN
D19  A:PMIC_IN_PWR_EN  in
D20  A:PMIC_IN_PB_IN
E1  F:NC
E2  F:NC
E3  F:NC
E4  F:NC
E5  G:VDDS_DDR
E6  A:SYS_RTC_1P8V
E7  G:VDDS_PLL
E8  B:VSSA_ADC
E9  A:SYS_VDD_1P8V
E10  G:VDDSHV_3P3V
E11  G:VDDSHV_3P3V
E12  G:VDDSHV_3P3V
E13  G:VDDSHV_3P3V
E14  A:SYS_RTC_1P8V
E15  C:UART0_RXD
E16  C:UART0_TXD
E17  C:UART0_RTSN
E18  C:UART0_CTSN
E19  E:VSS
E20  E:VSS
F1  F:NC
F2  F:NC
F3  F:NC
F4  F:NC
F5  G:VDDS_DDR
F6  G:VDD_CORE
F7  G:VDD_CORE
F8  E:VSS
F9  A:SYS_RTC_1P8V
F10  G:VDD_MPU
F11  G:VDD_MPU
F12  G:VDD_MPU
F13  G:VDD_MPU
F14  G:VDDSHV_3P3V
F15  B:USB1_DRVVBUS
F16  B:USB0_DRVVBUS
F17  C:MMC0_DAT3
F18  C:MMC0_DAT2
F19  E:VSS
F20  B:OSC1_OUT
G1  F:NC
G2  F:NC
G3  F:NC
G4  F:NC
G5  G:VDDS_DDR
G6  G:VDD_CORE
G7  G:VDD_CORE
G8  E:VSS
G9  E:VSS
G10  G:VDD_CORE
G11  E:VSS
G12  E:VSS
G13  G:VDD_MPU
G14  G:VDDSHV_3P3V
G15  C:MMC0_DAT1
G16  C:MMC0_DAT0
G17  C:MMC0_CLK
G18  C:MMC0_CMD
G19  E:VSS
G20  B:OSC1_GND
H1  F:NC
H2  F:NC
H3  F:NC
H4  F:NC
H5  G:VDDS_DDR
H6  E:VSS
H7  E:VSS
H8  E:VSS
H9  E:VSS
H10  E:VSS
H11  G:VDD_CORE
H12  E:VSS
H13  G:VDD_MPU
H14  G:VDDSHV_3P3V
H15  G:VDDS_PLL
H16  D:MII1_COL
H17  D:MII1_CRS
H18  D:RMII1_REF_CLK
H19  E:VSS
H20  B:OSC1_IN
J1  F:NC
J2  F:NC
J3  F:NC
J4  F:NC
J5  G:VDDS_DDR
J6  E:VSS
J7  E:VSS
J8  E:VSS
J9  E:VSS
J10  E:VSS
J11  E:VSS
J12  G:VDD_CORE
J13  G:VDD_MPU
J14  G:VDDSHV_3P3V
J15  D:MII1_RX_ER
J16  D:MII1_TX_EN
J17  D:MII1_RX_DV
J18  D:MII1_TXD3
J19  E:VSS
J20  E:VSS
K1  F:NC
K2  F:NC
K3  F:NC
K4  F:NC
K5  G:VDDS_DDR
K6  G:VDD_CORE
K7  E:VSS
K8  G:VDD_CORE
K9  E:VSS
K10  E:VSS
K11  E:VSS
K12  G:VDD_CORE
K13  A:SYS_RTC_1P8V
K14  G:VDDSHV_3P3V
K15  D:MII1_TXD2
K16  D:MII1_TXD1
K17  D:MII1_TXD0
K18  D:MII1_TX_CLK
K19  E:VSS
K20  B:OSC0_OUT
L1  F:NC
L2  F:NC
L3  F:NC
L4  F:NC
L5  G:VDDS_DDR
L6  G:VDD_CORE
L7  G:VDD_CORE
L8  G:VDD_CORE
L9  G:VDD_CORE
L10  E:VSS
L11  E:VSS
L12  E:VSS
L13  E:VSS
L14  G:VDDSHV_3P3V
L15  D:MII1_RXD1
L16  D:MII1_RXD2
L17  D:MII1_RXD3
L18  D:MII1_RX_CLK
L19  E:VSS
L20  B:OSC0_GND
M1  F:NC
M2  F:NC
M3  F:NC
M4  F:NC
M5  G:VPP
M6  E:VSS
M7  E:VSS
M8  E:VSS
M9  E:VSS
M10  E:VSS
M11  G:VDD_CORE
M12  E:VSS
M13  G:VDD_CORE
M14  E:VSS
M15  B:USB0_CE
M16  D:MII1_RXD0
M17  D:MDIO
M18  D:MDC
M19  E:VSS
M20  B:OSC0_IN
N1  F:NC
N2  F:NC
N3  F:NC
N4  F:NC
N5  G:VDDSHV_3P3V
N6  A:SYS_RTC_1P8V
N7  E:VSS
N8  G:VDD_CORE
N9  G:VDD_CORE
N10  E:VSS
N11  E:VSS
N12  G:VDD_CORE
N13  G:VDD_CORE
N14  E:VSS
N15  G:VDDSHV_3P3V
N16  A:SYS_VDD_1P8V
N17  B:USB0_DP
N18  B:USB0_DM
N19  E:VSS
N20  E:VSS
P1  F:NC
P2  F:NC
P3  F:NC
P4  F:NC
P5  G:VDDSHV_3P3V
P6  G:VDDSHV_3P3V
P7  G:VDDSHV_3P3V
P8  G:VDDSHV_3P3V
P9  A:SYS_RTC_1P8V
P10  G:VDDSHV_3P3V
P11  G:VDDSHV_3P3V
P12  G:VDDSHV_3P3V
P13  G:VDDSHV_3P3V
P14  A:SYS_RTC_1P8V
P15  B:USB0_VBUS
P16  B:USB0_ID
P17  B:USB1_ID
P18  B:USB1_CE
P19  E:VSS
P20  E:VSS
R1  D:LCD_DATA00
R2  D:LCD_DATA01
R3  D:LCD_DATA02
R4  D:LCD_DATA03
R5  D:LCD_HSYNC
R6  D:LCD_AC_BIAS_EN
R7  C:GPMC_ADVN_ALE
R8  C:GPMC_AD02
R9  C:GPMC_AD06
R10  G:VDDS_PLL
R11  G:VDDS_PLL
R12  C:GPMC_AD13
R13  C:GPMC_A00
R14  C:GPMC_A04
R15  G:VDDSHV_3P3V
R16  A:SYS_VDD_1P8V
R17  B:USB1_DP
R18  B:USB1_DM
R19  E:VSS
R20  E:VSS
T1  D:LCD_DATA04
T2  D:LCD_DATA05
T3  D:LCD_DATA06
T4  D:LCD_DATA07
T5  D:LCD_DATA15
T6  C:GPMC_BEN0_CLE
T7  C:GPMC_OEN_REN
T8  C:GPMC_AD03
T9  C:GPMC_AD07
T10  C:GPMC_AD09
T11  C:GPMC_AD10
T12  C:GPMC_AD12
T13  C:GPMC_CSN3
T14  C:GPMC_A03
T15  C:GPMC_A07
T16  C:GPMC_A10
T17  C:GPMC_WAIT0
T18  B:USB1_VBUS
T19  E:VSS
T20  E:VSS
U1  D:LCD_DATA08
U2  D:LCD_DATA09
U3  D:LCD_DATA10
U4  D:LCD_DATA11
U5  D:LCD_VSYNC
U6  C:GPMC_WEN
U7  C:GPMC_AD00
U8  C:GPMC_AD04
U9  C:GPMC_CSN1
U10  C:GPMC_AD08
U11  F:NC
U12  C:GPMC_AD11
U13  C:GPMC_AD15
U14  C:GPMC_A02
U15  C:GPMC_A06
U16  C:GPMC_A09
U17  C:GPMC_WPN
U18  C:GPMC_BEN1
U19  E:VSS
U20  A:SYS_VDD1_3P3V
V1  E:VSS
V2  D:LCD_DATA12
V3  D:LCD_DATA13
V4  D:LCD_DATA14
V5  D:LCD_PCLK
V6  C:GPMC_CSN0
V7  C:GPMC_AD01
V8  C:GPMC_AD05
V9  C:GPMC_CSN2
V10  F:NC
V11  F:NC
V12  C:GPMC_CLK
V13  C:GPMC_AD14
V14  C:GPMC_A01
V15  C:GPMC_A05
V16  C:GPMC_A08
V17  C:GPMC_A11
V18  E:VSS
V19  E:VSS
V20  A:SYS_VDD1_3P3V
W1  A:BAT_TEMP
W2  E:VSS
W3  E:VSS
W4  A:SYS_VOUT
W5  E:VSS
W6  E:VSS
W7  E:VSS
W8  E:VSS
W9  E:VSS
W10  E:VSS
W11  E:VSS
W12  E:VSS
W13  E:VSS
W14  E:VSS
W15  E:VSS
W16  E:VSS
W17  E:VSS
W18  E:VSS
W19  E:VSS
W20  E:VSS
Y1  A:BAT_VOLT
Y2  A:VIN_BAT
Y3  A:VIN_BAT
Y4  A:SYS_VOUT
Y5  A:VIN_AC
Y6  A:VIN_AC
Y7  E:VSS
Y8  A:VIN_USB
Y9  A:VIN_USB
Y10  E:VSS
Y11  A:SYS_VDD2_3P3V
Y12  E:VSS
Y13  G:EXTL1A
Y14  G:EXTL1B
Y15  E:VSS
Y16  G:EXTL2A
Y17  G:EXTL2B
Y18  E:VSS
Y19  G:EXTL3A
Y20  G:EXTL3B

## Footprint OSD335X-BGA-400 (pad centres in mm)
smd 0.5 x 0.5: A1 -12.065,-12.065; A2 -12.065,-10.795; A3 -12.065,-9.525; A4 -12.065,-8.255; A5 -12.065,-6.985; A6 -12.065,-5.715; A7 -12.065,-4.445; A8 -12.065,-3.175; A9 -12.065,-1.905; A10 -12.065,-0.635; A11 -12.065,0.635; A12 -12.065,1.905; A13 -12.065,3.175; A14 -12.065,4.445; A15 -12.065,5.715; A16 -12.065,6.985; A17 -12.065,8.255; A18 -12.065,9.525; A19 -12.065,10.795; A20 -12.065,12.065; B1 -10.795,-12.065; B2 -10.795,-10.795; B3 -10.795,-9.525; B4 -10.795,-8.255; B5 -10.795,-6.985; B6 -10.795,-5.715; B7 -10.795,-4.445; B8 -10.795,-3.175; B9 -10.795,-1.905; B10 -10.795,-0.635; B11 -10.795,0.635; B12 -10.795,1.905; B13 -10.795,3.175; B14 -10.795,4.445; B15 -10.795,5.715; B16 -10.795,6.985; B17 -10.795,8.255; B18 -10.795,9.525; B19 -10.795,10.795; B20 -10.795,12.065; C1 -9.525,-12.065; C2 -9.525,-10.795; C3 -9.525,-9.525; C4 -9.525,-8.255; C5 -9.525,-6.985; C6 -9.525,-5.715; C7 -9.525,-4.445; C8 -9.525,-3.175; C9 -9.525,-1.905; C10 -9.525,-0.635; C11 -9.525,0.635; C12 -9.525,1.905; C13 -9.525,3.175; C14 -9.525,4.445; C15 -9.525,5.715; C16 -9.525,6.985; C17 -9.525,8.255; C18 -9.525,9.525; C19 -9.525,10.795; C20 -9.525,12.065; D1 -8.255,-12.065; D2 -8.255,-10.795; D3 -8.255,-9.525; D4 -8.255,-8.255; D5 -8.255,-6.985; D6 -8.255,-5.715; D7 -8.255,-4.445; D8 -8.255,-3.175; D9 -8.255,-1.905; D10 -8.255,-0.635; D11 -8.255,0.635; D12 -8.255,1.905; D13 -8.255,3.175; D14 -8.255,4.445; D15 -8.255,5.715; D16 -8.255,6.985; D17 -8.255,8.255; D18 -8.255,9.525; D19 -8.255,10.795; D20 -8.255,12.065; E1 -6.985,-12.065; E2 -6.985,-10.795; E3 -6.985,-9.525; E4 -6.985,-8.255; E5 -6.985,-6.985; E6 -6.985,-5.715; E7 -6.985,-4.445; E8 -6.985,-3.175; E9 -6.985,-1.905; E10 -6.985,-0.635; E11 -6.985,0.635; E12 -6.985,1.905; E13 -6.985,3.175; E14 -6.985,4.445; E15 -6.985,5.715; E16 -6.985,6.985; E17 -6.985,8.255; E18 -6.985,9.525; E19 -6.985,10.795; E20 -6.985,12.065; F1 -5.715,-12.065; F2 -5.715,-10.795; F3 -5.715,-9.525; F4 -5.715,-8.255; F5 -5.715,-6.985; F6 -5.715,-5.715; F7 -5.715,-4.445; F8 -5.715,-3.175; F9 -5.715,-1.905; F10 -5.715,-0.635; F11 -5.715,0.635; F12 -5.715,1.905; F13 -5.715,3.175; F14 -5.715,4.445; F15 -5.715,5.715; F16 -5.715,6.985; F17 -5.715,8.255; F18 -5.715,9.525; F19 -5.715,10.795; F20 -5.715,12.065; G1 -4.445,-12.065; G2 -4.445,-10.795; G3 -4.445,-9.525; G4 -4.445,-8.255; G5 -4.445,-6.985; G6 -4.445,-5.715; G7 -4.445,-4.445; G8 -4.445,-3.175; G9 -4.445,-1.905; G10 -4.445,-0.635; G11 -4.445,0.635; G12 -4.445,1.905; G13 -4.445,3.175; G14 -4.445,4.445; G15 -4.445,5.715; G16 -4.445,6.985; G17 -4.445,8.255; G18 -4.445,9.525; G19 -4.445,10.795; G20 -4.445,12.065; H1 -3.175,-12.065; H2 -3.175,-10.795; H3 -3.175,-9.525; H4 -3.175,-8.255; H5 -3.175,-6.985; H6 -3.175,-5.715; H7 -3.175,-4.445; H8 -3.175,-3.175; H9 -3.175,-1.905; H10 -3.175,-0.635; H11 -3.175,0.635; H12 -3.175,1.905; H13 -3.175,3.175; H14 -3.175,4.445; H15 -3.175,5.715; H16 -3.175,6.985; H17 -3.175,8.255; H18 -3.175,9.525; H19 -3.175,10.795; H20 -3.175,12.065; J1 -1.905,-12.065; J2 -1.905,-10.795; J3 -1.905,-9.525; J4 -1.905,-8.255; J5 -1.905,-6.985; J6 -1.905,-5.715; J7 -1.905,-4.445; J8 -1.905,-3.175; J9 -1.905,-1.905; J10 -1.905,-0.635; J11 -1.905,0.635; J12 -1.905,1.905; J13 -1.905,3.175; J14 -1.905,4.445; J15 -1.905,5.715; J16 -1.905,6.985; J17 -1.905,8.255; J18 -1.905,9.525; J19 -1.905,10.795; J20 -1.905,12.065; K1 -0.635,-12.065; K2 -0.635,-10.795; K3 -0.635,-9.525; K4 -0.635,-8.255; K5 -0.635,-6.985; K6 -0.635,-5.715; K7 -0.635,-4.445; K8 -0.635,-3.175; K9 -0.635,-1.905; K10 -0.635,-0.635; K11 -0.635,0.635; K12 -0.635,1.905; K13 -0.635,3.175; K14 -0.635,4.445; K15 -0.635,5.715; K16 -0.635,6.985; K17 -0.635,8.255; K18 -0.635,9.525; K19 -0.635,10.795; K20 -0.635,12.065; L1 0.635,-12.065; L2 0.635,-10.795; L3 0.635,-9.525; L4 0.635,-8.255; L5 0.635,-6.985; L6 0.635,-5.715; L7 0.635,-4.445; L8 0.635,-3.175; L9 0.635,-1.905; L10 0.635,-0.635; L11 0.635,0.635; L12 0.635,1.905; L13 0.635,3.175; L14 0.635,4.445; L15 0.635,5.715; L16 0.635,6.985; L17 0.635,8.255; L18 0.635,9.525; L19 0.635,10.795; L20 0.635,12.065; M1 1.905,-12.065; M2 1.905,-10.795; M3 1.905,-9.525; M4 1.905,-8.255; M5 1.905,-6.985; M6 1.905,-5.715; M7 1.905,-4.445; M8 1.905,-3.175; M9 1.905,-1.905; M10 1.905,-0.635; M11 1.905,0.635; M12 1.905,1.905; M13 1.905,3.175; M14 1.905,4.445; M15 1.905,5.715; M16 1.905,6.985; M17 1.905,8.255; M18 1.905,9.525; M19 1.905,10.795; M20 1.905,12.065; N1 3.175,-12.065; N2 3.175,-10.795; N3 3.175,-9.525; N4 3.175,-8.255; N5 3.175,-6.985; N6 3.175,-5.715; N7 3.175,-4.445; N8 3.175,-3.175; N9 3.175,-1.905; N10 3.175,-0.635; N11 3.175,0.635; N12 3.175,1.905; N13 3.175,3.175; N14 3.175,4.445; N15 3.175,5.715; N16 3.175,6.985; N17 3.175,8.255; N18 3.175,9.525; N19 3.175,10.795; N20 3.175,12.065; P1 4.445,-12.065; P2 4.445,-10.795; P3 4.445,-9.525; P4 4.445,-8.255; P5 4.445,-6.985; P6 4.445,-5.715; P7 4.445,-4.445; P8 4.445,-3.175; P9 4.445,-1.905; P10 4.445,-0.635; P11 4.445,0.635; P12 4.445,1.905; P13 4.445,3.175; P14 4.445,4.445; P15 4.445,5.715; P16 4.445,6.985; P17 4.445,8.255; P18 4.445,9.525; P19 4.445,10.795; P20 4.445,12.065; R1 5.715,-12.065; R2 5.715,-10.795; R3 5.715,-9.525; R4 5.715,-8.255; R5 5.715,-6.985; R6 5.715,-5.715; R7 5.715,-4.445; R8 5.715,-3.175; R9 5.715,-1.905; R10 5.715,-0.635; R11 5.715,0.635; R12 5.715,1.905; R13 5.715,3.175; R14 5.715,4.445; R15 5.715,5.715; R16 5.715,6.985; R17 5.715,8.255; R18 5.715,9.525; R19 5.715,10.795; R20 5.715,12.065; T1 6.985,-12.065; T2 6.985,-10.795; T3 6.985,-9.525; T4 6.985,-8.255; T5 6.985,-6.985; T6 6.985,-5.715; T7 6.985,-4.445; T8 6.985,-3.175; T9 6.985,-1.905; T10 6.985,-0.635; T11 6.985,0.635; T12 6.985,1.905; T13 6.985,3.175; T14 6.985,4.445; T15 6.985,5.715; T16 6.985,6.985; T17 6.985,8.255; T18 6.985,9.525; T19 6.985,10.795; T20 6.985,12.065; U1 8.255,-12.065; U2 8.255,-10.795; U3 8.255,-9.525; U4 8.255,-8.255; U5 8.255,-6.985; U6 8.255,-5.715; U7 8.255,-4.445; U8 8.255,-3.175; U9 8.255,-1.905; U10 8.255,-0.635; U11 8.255,0.635; U12 8.255,1.905; U13 8.255,3.175; U14 8.255,4.445; U15 8.255,5.715; U16 8.255,6.985; U17 8.255,8.255; U18 8.255,9.525; U19 8.255,10.795; U20 8.255,12.065; V1 9.525,-12.065; V2 9.525,-10.795; V3 9.525,-9.525; V4 9.525,-8.255; V5 9.525,-6.985; V6 9.525,-5.715; V7 9.525,-4.445; V8 9.525,-3.175; V9 9.525,-1.905; V10 9.525,-0.635; V11 9.525,0.635; V12 9.525,1.905; V13 9.525,3.175; V14 9.525,4.445; V15 9.525,5.715; V16 9.525,6.985; V17 9.525,8.255; V18 9.525,9.525; V19 9.525,10.795; V20 9.525,12.065; W1 10.795,-12.065; W2 10.795,-10.795; W3 10.795,-9.525; W4 10.795,-8.255; W5 10.795,-6.985; W6 10.795,-5.715; W7 10.795,-4.445; W8 10.795,-3.175; W9 10.795,-1.905; W10 10.795,-0.635; W11 10.795,0.635; W12 10.795,1.905; W13 10.795,3.175; W14 10.795,4.445; W15 10.795,5.715; W16 10.795,6.985; W17 10.795,8.255; W18 10.795,9.525; W19 10.795,10.795; W20 10.795,12.065; Y1 12.065,-12.065; Y2 12.065,-10.795; Y3 12.065,-9.525; Y4 12.065,-8.255; Y5 12.065,-6.985; Y6 12.065,-5.715; Y7 12.065,-4.445; Y8 12.065,-3.175; Y9 12.065,-1.905; Y10 12.065,-0.635; Y11 12.065,0.635; Y12 12.065,1.905; Y13 12.065,3.175; Y14 12.065,4.445; Y15 12.065,5.715; Y16 12.065,6.985; Y17 12.065,8.255; Y18 12.065,9.525; Y19 12.065,10.795; Y20 12.065,12.065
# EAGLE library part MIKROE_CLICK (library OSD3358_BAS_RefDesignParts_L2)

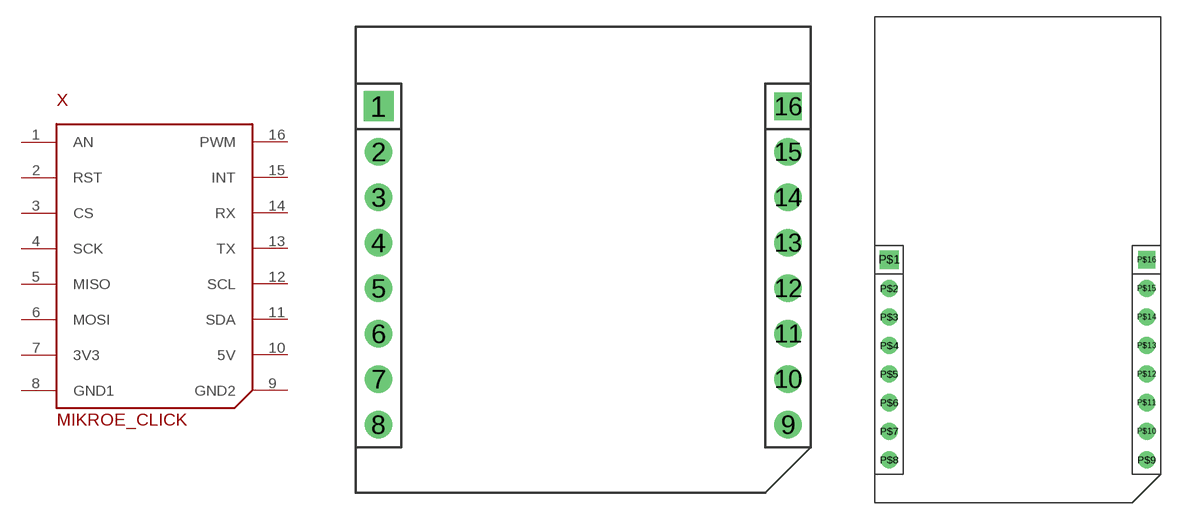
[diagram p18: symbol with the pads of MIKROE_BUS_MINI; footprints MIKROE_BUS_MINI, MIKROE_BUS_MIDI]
Designator prefix X

## MIKROE_CLICKMINI  [MIKROE_BUS_MINI]
1  AN
2  RST
3  CS
4  SCK
5  MISO
6  MOSI
7  3V3
8  GND1
9  GND2
10  5V
11  SDA
12  SCL
13  TX
14  RX
15  INT
16  PWM

## MIKROE_CLICKMIDI  [MIKROE_BUS_MIDI]
P$1  AN
P$2  RST
P$3  CS
P$4  SCK
P$5  MISO
P$6  MOSI
P$7  3V3
P$8  GND1
P$9  GND2
P$10  5V
P$11  SDA
P$12  SCL
P$13  TX
P$14  RX
P$15  INT
P$16  PWM

## MIKROE_CLICKLARGE  [MIKROE_BUS_LARGE]
Pads as for MIKROE_BUS_MIDI

## Footprint MIKROE_BUS_MINI (pad centres in mm)
drill 0.889 pad 1.676 square: 1 1.27,21.59
drill 0.889 pad 1.524: 2 1.27,19.05; 3 1.27,16.51; 4 1.27,13.97; 5 1.27,11.43; 6 1.27,8.89; 7 1.27,6.35; 8 1.27,3.81; 9 24.13,3.81; 10 24.13,6.35; 11 24.13,8.89; 12 24.13,11.43; 13 24.13,13.97; 14 24.13,16.51; 15 24.13,19.05
drill 0.889 pad 1.524 square: 16 24.13,21.59

## Footprint MIKROE_BUS_MIDI (pad centres in mm)
drill 0.889 pad 1.676 square: P$1 1.27,21.59
drill 0.889 pad 1.524: P$2 1.27,19.05; P$3 1.27,16.51; P$4 1.27,13.97; P$5 1.27,11.43; P$6 1.27,8.89; P$7 1.27,6.35; P$8 1.27,3.81; P$9 24.13,3.81; P$10 24.13,6.35; P$11 24.13,8.89; P$12 24.13,11.43; P$13 24.13,13.97; P$14 24.13,16.51; P$15 24.13,19.05
drill 0.889 pad 1.524 square: P$16 24.13,21.59

## Footprint MIKROE_BUS_LARGE (pad centres in mm)
drill 0.889 pad 1.676 square: P$1 1.27,21.59
drill 0.889 pad 1.524: P$2 1.27,19.05; P$3 1.27,16.51; P$4 1.27,13.97; P$5 1.27,11.43; P$6 1.27,8.89; P$7 1.27,6.35; P$8 1.27,3.81; P$9 24.13,3.81; P$10 24.13,6.35; P$11 24.13,8.89; P$12 24.13,11.43; P$13 24.13,13.97; P$14 24.13,16.51; P$15 24.13,19.05
drill 0.889 pad 1.524 square: P$16 24.13,21.59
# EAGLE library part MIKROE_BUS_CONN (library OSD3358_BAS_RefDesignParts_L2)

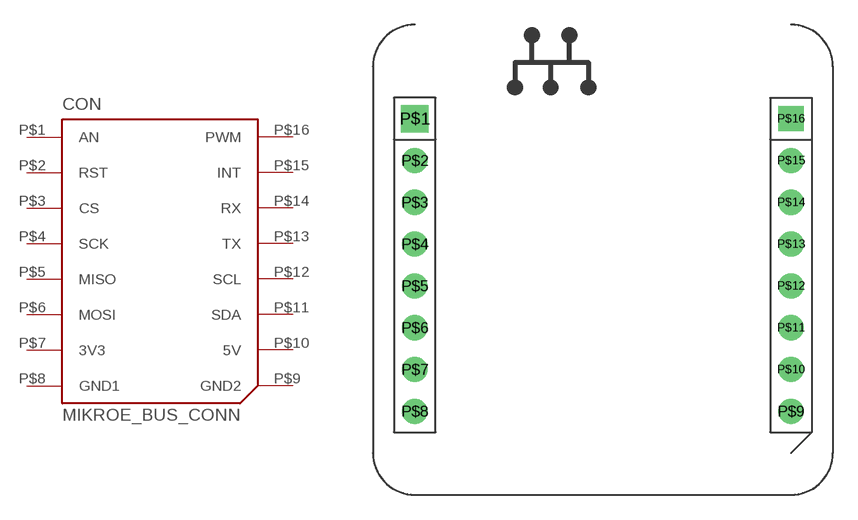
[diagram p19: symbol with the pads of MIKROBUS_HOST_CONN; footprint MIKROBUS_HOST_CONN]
Designator prefix CON

## MIKROE_BUS_CONN  [MIKROBUS_HOST_CONN]
P$1  AN
P$2  RST
P$3  CS
P$4  SCK
P$5  MISO
P$6  MOSI
P$7  3V3
P$8  GND1
P$9  GND2
P$10  5V
P$11  SDA
P$12  SCL
P$13  TX
P$14  RX
P$15  INT
P$16  PWM

## Footprint MIKROBUS_HOST_CONN (pad centres in mm)
drill 0.889 pad 1.676 square: P$1 0,0
drill 0.889 pad 1.524: P$2 0,-2.54; P$3 0,-5.08; P$4 0,-7.62; P$5 0,-10.16; P$6 0,-12.7; P$7 0,-15.24; P$8 0,-17.78; P$9 22.86,-17.78; P$10 22.86,-15.24; P$11 22.86,-12.7; P$12 22.86,-10.16; P$13 22.86,-7.62; P$14 22.86,-5.08; P$15 22.86,-2.54
drill 0.889 pad 1.524 square: P$16 22.86,0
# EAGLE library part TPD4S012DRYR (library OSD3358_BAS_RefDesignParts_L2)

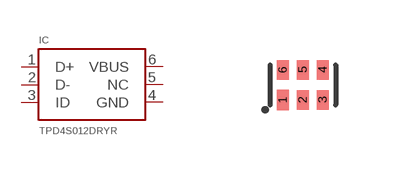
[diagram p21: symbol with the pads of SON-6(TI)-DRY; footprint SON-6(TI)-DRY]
Designator prefix IC

## TPD4S012DRYR  [SON-6(TI)-DRY]
1  D+
2  D-
3  ID
4  GND
5  NC
6  VBUS

## Footprint SON-6(TI)-DRY (pad centres in mm)
smd 0.3 x 0.52: 1 -0.5,-0.38
smd 0.3 x 0.49: 2 0,-0.375; 3 0.5,-0.375; 4 0.5,0.375; 5 0,0.375; 6 -0.5,0.375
